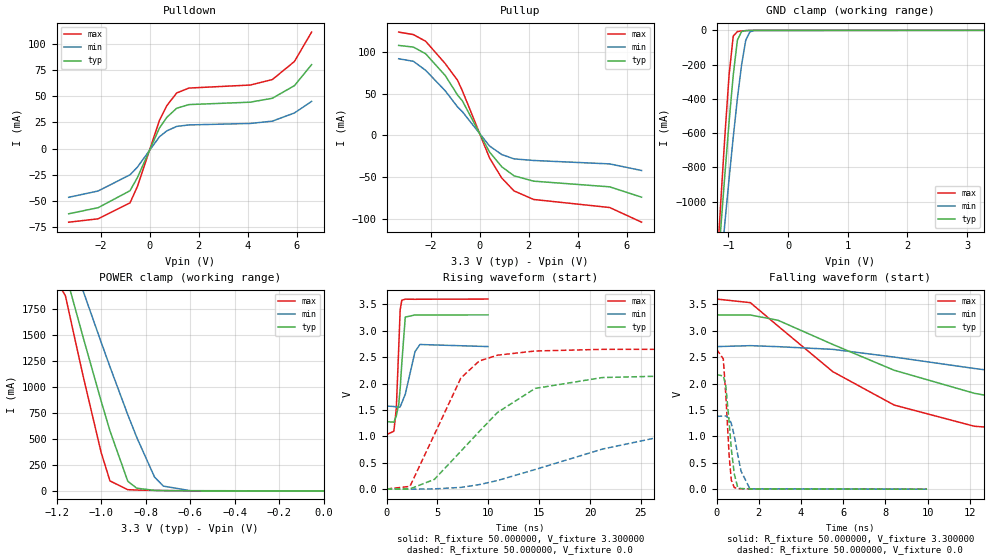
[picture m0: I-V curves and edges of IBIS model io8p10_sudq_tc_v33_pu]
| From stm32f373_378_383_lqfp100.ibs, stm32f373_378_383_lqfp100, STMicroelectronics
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|   Model io8p10_sudq_tc_v33_pu
[Model]  io8p10_sudq_tc_v33_pu
Model_type I/O
Polarity   Non-Inverting
Enable   Active-Low
Vinl =   0.990000V
Vinh =   2.310000V
Vmeas =  1.650000V
Cref =   50.000000pF
Rref =   100.000000M
Vref =   0.0V
C_comp   1.325200pF   1.251200pF   1.426700pF
[Temperature Range]   25.000000   0.125000k   -40.000000
[Pullup Reference]   3.300000V   2.700000V   3.600000V
[Pulldown Reference]   0.0V   0.0V   0.0V
[POWER Clamp Reference]   3.300000V   2.700000V   3.600000V
[GND Clamp Reference]   0.0V   0.0V   0.0V
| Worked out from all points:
|   slope of the pulldown table from 0 to 0.495 V, typ, clamps not added: 21.3 ohm
|   slope of the pullup table from 0 to 0.495 V, typ, clamps not added: 20.9 ohm
|   GND clamp passes 1 mA (typ) near -0.67 V on its own axis
|   POWER clamp passes 1 mA (typ) near -0.60 V on its own axis
|   rising waveform, R_fixture 50.000000, V_fixture 3.300000: 20-80 % time 415ps typ, 825ps min, 303ps max; typ from 1.28 V to 3.3 V
|   rising waveform, R_fixture 50.000000, V_fixture 0.0: 20-80 % time 6.87ns typ, 16.4ns min, 3.73ns max; typ from 0.001 V to 2.17 V
|   falling waveform, R_fixture 50.000000, V_fixture 3.300000: 20-80 % time 9.33ns typ, 15.5ns min, 5.81ns max; typ from 3.3 V to 1.28 V
|   falling waveform, R_fixture 50.000000, V_fixture 0.0: 20-80 % time 298ps typ, 414ps min, 226ps max; typ from 2.17 V to 0.001 V
[Pulldown]
|Voltage   I(typ)   I(min)   I(max)
-3.3V     -62mA      -46.3mA    -70mA
-2.1V     -56.2mA    -40.3mA    -66.8mA
-800mV    -40.05mA   -24.9mA    -51.58mA
-500mV    -27.57mA   -17.6mA    -36.07mA
400mV     19.71mA    11.36mA    27.01mA
700mV     29.83mA    16.93mA    40.97mA
1.1V      38.46mA    21.2mA     53.02mA
1.6V      41.98mA    22.62mA    57.7mA
4.1V      44.26mA    24mA       60.59mA
5V        48mA       26.2mA     65.8mA
5.9V      60mA       34mA       83mA
6.6V      80mA       45mA       111mA
[Pullup]
|Voltage   I(typ)   I(min)   I(max)
-3.3V     108mA      92mA       124mA
-2.7V     106mA      89mA       121mA
-2.2V     98mA       78.1mA     113mA
-1.4V     71.8mA     53.5mA     86.1mA
-900mV    48.5mA     34.23mA    66.14mA
-700mV    41.33mA    28.36mA    53.31mA
400mV     -19.77mA   -12.52mA   -26.8mA
900mV     -37.48mA   -22.89mA   -50.99mA
1.4V      -48.39mA   -28.06mA   -66.43mA
2.2V      -54.79mA   -29.98mA   -76.75mA
5.3V      -61.6mA    -34.1mA    -86.4mA
6.6V      -74mA      -42mA      -104mA
[GND_clamp]
|Voltage   I(typ)   I(min)   I(max)
-3.3V     -9.739A    -9.975A    -9.587A
-1.2V     -1.489A    -1.65A     -1.416A
-1.13V    -1.162A    -1.385A    -1.009A
-1.06V    -842.2mA   -1.125A    -616.9mA
-990mV    -537.1mA   -870.1mA   -263mA
-920mV    -262.4mA   -625.3mA   -33.96mA
-850mV    -56.94mA   -397.4mA   -7.08mA
-780mV    -7.011mA   -202.2mA   -3.71mA
-710mV    -1.778mA   -58.23mA   -1.736mA
-640mV    -550uA     -8.783mA   -542.4uA
-570mV    -109.8uA   -1.292mA   -86.89uA
3.28V     0A         0A         0A
[POWER_clamp]
|Voltage   I(typ)   I(min)   I(max)
-3.28V    9.897A     9.838A     9.594A
-1.16V    2.103A     2.419A     1.88A
-1.12V    1.788A     2.17A      1.488A
-1.08V    1.476A     1.923A     1.102A
-1V       868.2mA    1.435A     373.1mA
-960mV    578.3mA    1.196A     96.08mA
-880mV    93.25mA    734.2mA    12.03mA
-840mV    26.31mA    517.4mA    8.576mA
-760mV    5.12mA     134mA      5.134mA
-720mV    3.368mA    46.35mA    3.823mA
-600mV    1.018mA    2.575mA    1.086mA
0V        0A         0A         0A
[Ramp]
| variable   typ   min   max
dV/dt_r  1.30037/6.85912n   0.81167/16.46555n   1.58858/3.72403n
dV/dt_f  1.21374/9.31880n   0.66888/15.57260n   1.54152/5.80485n
R_load = 50.000000
[Rising Waveform]
R_fixture= 50.000000
V_fixture= 3.300000
V_fixture_min= 2.700000
V_fixture_max= 3.600000
|time   V(typ)   V(min)   V(max)
0s        1.277V     1.572V     1.031V
720.7ps   1.267V     1.565V     1.096V
961ps     1.385V     1.553V     1.52V
1.201ns   1.606V     1.55V      2.688V
1.341ns   1.904V     1.556V     3.397V
1.502ns   2.384V     1.633V     3.579V
1.842ns   3.259V     1.797V     3.598V
2.803ns   3.299V     2.605V     3.596V
3.283ns   3.299V     2.739V     3.597V
9.97ns    3.3V       2.7V       3.6V
[Rising Waveform]
R_fixture= 50.000000
V_fixture= 0.0
V_fixture_min= 0.0
V_fixture_max= 0.0
|time   V(typ)   V(min)   V(max)
0s        1.014mV    1.116mV    973.4uV
2.302ns   2.866mV    -2.155mV   50.76mV
4.705ns   183.5mV    3.128mV    1.034V
7.307ns   716.5mV    31.32mV    2.104V
9.109ns   1.09V      83.87mV    2.426V
10.91ns   1.452V     161.9mV    2.537V
14.61ns   1.907V     370.4mV    2.616V
21.22ns   2.113V     757.4mV    2.647V
31.43ns   2.16V      1.171V     2.649V
49.85ns   2.168V     1.379V     2.649V
[Falling Waveform]
R_fixture= 50.000000
V_fixture= 3.300000
V_fixture_min= 2.700000
V_fixture_max= 3.600000
|time   V(typ)   V(min)   V(max)
0s        3.3V       2.7V       3.6V
1.602ns   3.298V     2.718V     3.532V
2.903ns   3.2V       2.699V     3.092V
5.506ns   2.741V     2.648V     2.226V
8.408ns   2.253V     2.502V     1.594V
12.21ns   1.816V     2.286V     1.192V
15.82ns   1.558V     2.102V     1.088V
20.62ns   1.388V     1.915V     1.05V
35.14ns   1.283V     1.627V     1.032V
49.85ns   1.277V     1.572V     1.031V
[Falling Waveform]
R_fixture= 50.000000
V_fixture= 0.0
V_fixture_min= 0.0
V_fixture_max= 0.0
|time   V(typ)   V(min)   V(max)
0s        2.168V     1.379V     2.649V
320.3ps   2.146V     1.384V     2.469V
440.4ps   1.957V     1.386V     1.782V
600.6ps   1.257V     1.343V     615.9mV
700.7ps   760.8mV    1.243V     171.8mV
840.8ps   289.8mV    1.011V     32mV
1.001ns   35.36mV    659.4mV    11.73mV
1.161ns   12.95mV    341.7mV    6.946mV
1.582ns   4.539mV    7.242mV    5.834mV
9.97ns    1.014mV    1.116mV    973.4uV
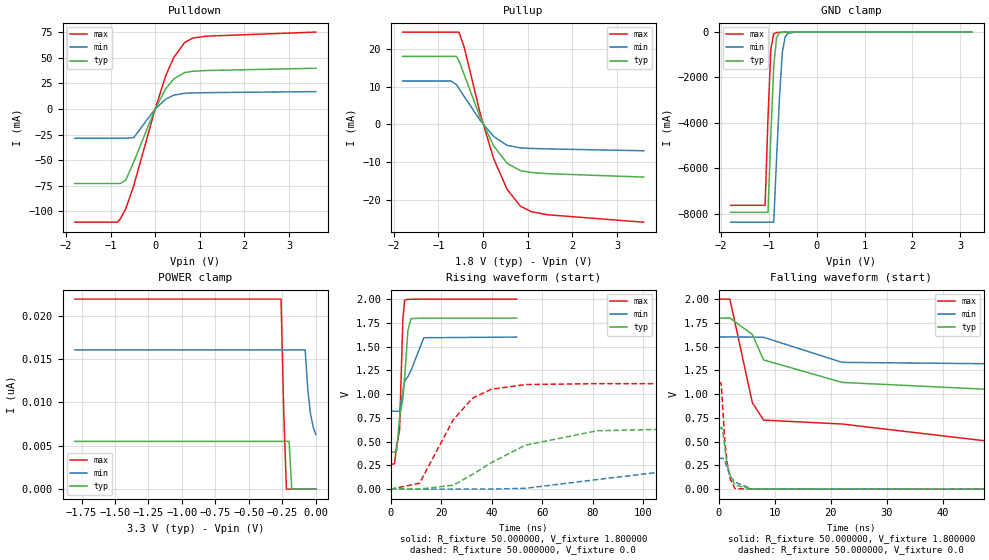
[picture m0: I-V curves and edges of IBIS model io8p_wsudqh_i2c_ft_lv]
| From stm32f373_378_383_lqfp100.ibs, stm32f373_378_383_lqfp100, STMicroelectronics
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|   Model io8p_wsudqh_i2c_ft_lv
[Model]  io8p_wsudqh_i2c_ft_lv
Model_type I/O
Polarity   Non-Inverting
Enable   Active-Low
Vinl =   0.540000V
Vinh =   1.260000V
Vmeas =  0.900000V
Cref =   40.000000pF
Rref =   100.000000M
Vref =   0.0V
C_comp   0.0F   0.0F   0.0F
[Temperature Range]   25.000000   0.140000k   -40.000000
[Pullup Reference]   1.800000V   1.600000V   2.000000V
[Pulldown Reference]   0.0V   0.0V   0.0V
[POWER Clamp Reference]   3.300000V   2.700000V   3.600000V
[GND Clamp Reference]   0.0V   0.0V   0.0V
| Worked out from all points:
|   slope of the pulldown table from 0 to 0.27 V, typ, clamps not added: 12.4 ohm
|   slope of the pullup table from 0 to 0.27 V, typ, clamps not added: 42.7 ohm
|   GND clamp passes 1 mA (typ) near -0.61 V on its own axis
|   rising waveform, R_fixture 50.000000, V_fixture 1.800000: 20-80 % time 3.36ns typ, 5.5ns min, 1.18ns max; typ from 0.39 V to 1.8 V
|   rising waveform, R_fixture 50.000000, V_fixture 0.0: 20-80 % time 28.5ns typ, 60ns min, 14.6ns max; typ from 0 V to 0.643 V
|   falling waveform, R_fixture 50.000000, V_fixture 1.800000: 20-80 % time 95.2ns typ, 220ns min, 38.6ns max; typ from 1.8 V to 0.39 V
|   falling waveform, R_fixture 50.000000, V_fixture 0.0: 20-80 % time 1.17ns typ, 1.76ns min, 975ps max; typ from 0.643 V to 0 V
[Pulldown]
|Voltage   I(typ)   I(min)   I(max)
-1.8V     -72.82mA   -28.67mA   -110.6mA
-840mV    -72.82mA   -28.67mA   -110.6mA
-780mV    -72.82mA   -28.67mA   -107.2mA
-660mV    -69.63mA   -28.67mA   -97.66mA
-480mV    -51.79mA   -27.98mA   -74.89mA
0V        0A         0A         0A
240mV     19.98mA    9.621mA    32.82mA
420mV     29.47mA    13.52mA    50.45mA
660mV     35.49mA    15.27mA    64.82mA
840mV     36.76mA    15.6mA     69.15mA
1.14V     37.47mA    15.86mA    71.04mA
3.6V      39.71mA    16.9mA     75.01mA
[Pullup]
|Voltage   I(typ)   I(min)   I(max)
-1.8V     18.1mA     11.56mA    24.57mA
-720mV    18.1mA     11.56mA    24.57mA
-600mV    18.1mA     10.62mA    24.57mA
-540mV    16.94mA    9.59mA     24.54mA
-420mV    13.15mA    7.37mA     20.4mA
-60mV     1.723mA    985.9uA    2.671mA
240mV     -5.743mA   -3.226mA   -9.221mA
540mV     -10.36mA   -5.558mA   -17.32mA
840mV     -12.32mA   -6.245mA   -21.78mA
1.08V     -12.77mA   -6.379mA   -23.2mA
1.44V     -13.09mA   -6.504mA   -24.02mA
3.6V      -14mA      -7mA       -26mA
[GND_clamp]
|Voltage   I(typ)   I(min)   I(max)
-1.8V     -7.944A    -8.38A     -7.635A
-1.08V    -7.944A    -8.38A     -7.635A
-1.02V    -7.944A    -8.38A     -3.818A
-960mV    -4.573A    -8.38A     -759.3mA
-900mV    -1.502A    -8.38A     -75.03mA
-840mV    -238mA     -5.574A    -20.4mA
-780mV    -36.12mA   -2.918A    -12.65mA
-720mV    -7.999mA   -894.2mA   -8.064mA
-660mV    -2.38mA    -209.5mA   -4.357mA
-600mV    -722.7uA   -49.62mA   -1.754mA
-420mV    -7.04uA    -712.1uA   -10.35uA
3.24V     0A         5.34nA     0A
[POWER_clamp]
|Voltage   I(typ)   I(min)   I(max)
-1.8V     5.515nA    16.06nA    21.93nA
-260mV    5.515nA    16.06nA    21.93nA
-240mV    5.515nA    16.06nA    8.985nA
-220mV    5.515nA    16.06nA    0A
-200mV    5.515nA    16.06nA    0A
-180mV    0A         16.06nA    0A
-80mV     0A         16.06nA    0A
-60mV     0A         11.42nA    0A
-40mV     0A         8.703nA    0A
-20mV     0A         7.161nA    0A
0V        0A         6.282nA    0A
[Ramp]
| variable   typ   min   max
dV/dt_r  0.38563/28.42811n   0.19292/59.39374n   0.66606/14.53010n
dV/dt_f  0.84326/94.87785n   0.39602/0.18874u   1.04521/38.27709n
R_load = 50.000000
[Rising Waveform]
R_fixture= 50.000000
V_fixture= 1.800000
V_fixture_min= 1.600000
V_fixture_max= 2.000000
|time   V(typ)   V(min)   V(max)
0s        389.9mV    821mV      258mV
1.502ns   388.9mV    819.7mV    267.3mV
2.402ns   406.2mV    818.3mV    463.2mV
3.504ns   755mV      820.6mV    617.3mV
4.805ns   944.7mV    1.022V     1.783V
5.506ns   1.17V      1.138V     1.988V
6.807ns   1.668V     1.183V     1.997V
8.008ns   1.794V     1.247V     1.998V
13.11ns   1.8V       1.593V     1.999V
49.85ns   1.8V       1.6V       2V
[Rising Waveform]
R_fixture= 50.000000
V_fixture= 0.0
V_fixture_min= 0.0
V_fixture_max= 0.0
|time   V(typ)   V(min)   V(max)
0s        973.9pV    20.22nV    702pV
11.41ns   -342.5uV   -776.4uV   62.09mV
24.72ns   40.77mV    -74.15uV   728.8mV
32.33ns   153.9mV    6.2uV      956.4mV
39.94ns   280.4mV    292.3uV    1.052V
53.25ns   462mV      8.25mV     1.1V
81.78ns   614.1mV    100.7mV    1.11V
131.2ns   642.1mV    256mV      1.11V
182.6ns   642.8mV    309.4mV    1.11V
947.1ns   642.7mV    322.7mV    1.11V
[Falling Waveform]
R_fixture= 50.000000
V_fixture= 1.800000
V_fixture_min= 1.600000
V_fixture_max= 2.000000
|time   V(typ)   V(min)   V(max)
0s        1.8V       1.6V       2V
2.002ns   1.801V     1.602V     2V
6.006ns   1.628V     1.6V       911.3mV
8.008ns   1.36V      1.598V     726.5mV
22.02ns   1.123V     1.334V     685.3mV
78.08ns   966.2mV    1.303V     296.2mV
116.1ns   543mV      1.296V     266.8mV
170.2ns   419.4mV    1.192V     259.3mV
340.3ns   390.6mV    850.8mV    257.9mV
997ns     389.9mV    821mV      258mV
[Falling Waveform]
R_fixture= 50.000000
V_fixture= 0.0
V_fixture_min= 0.0
V_fixture_max= 0.0
|time   V(typ)   V(min)   V(max)
0s        642.7mV    322.7mV    1.11V
400.4ps   646.9mV    323mV      1.119V
500.5ps   650.7mV    324.1mV    1.086V
700.7ps   624.1mV    327.7mV    889.6mV
1.101ns   438.9mV    298.8mV    513.3mV
1.502ns   258.1mV    226.9mV    286.1mV
2.102ns   132.4mV    132.6mV    100.1mV
2.903ns   42.85mV    74.38mV    6.502mV
5.906ns   1.079mV    1.846mV    589.7uV
49.85ns   973.9pV    20.22nV    702pV
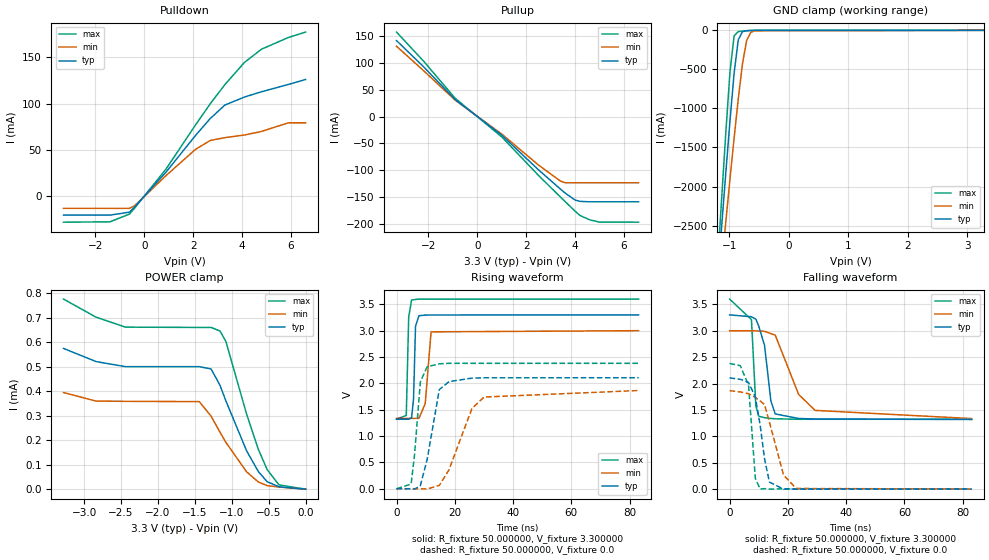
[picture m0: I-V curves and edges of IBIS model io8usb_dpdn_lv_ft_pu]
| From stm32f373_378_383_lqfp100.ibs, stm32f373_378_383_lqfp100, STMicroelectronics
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|   Model io8usb_dpdn_lv_ft_pu
[Model]  io8usb_dpdn_lv_ft_pu
Model_type I/O
Polarity   Non-Inverting
Enable   Active-Low
Vinl =   0.990000V
Vinh =   2.310000V
Vmeas =  1.650000V
Cref =   50.000000pF
Rref =   100.000000M
Vref =   0.0V
C_comp   5.029800pF   4.851400pF   5.238000pF
[Temperature Range]   25.000000   0.125000k   -40.000000
[Pullup Reference]   3.300000V   3.000000V   3.600000V
[Pulldown Reference]   0.0V   0.0V   0.0V
[POWER Clamp Reference]   3.300000V   3.000000V   3.600000V
[GND Clamp Reference]   0.0V   0.0V   0.0V
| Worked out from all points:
|   slope of the pulldown table from 0 to 0.495 V, typ, clamps not added: 34.5 ohm
|   slope of the pullup table from 0 to 0.495 V, typ, clamps not added: 30.3 ohm
|   GND clamp passes 1 mA (typ) near -0.59 V on its own axis
|   rising waveform, R_fixture 50.000000, V_fixture 3.300000: 20-80 % time 563ps typ, 845ps min, 473ps max; typ from 1.32 V to 3.3 V
|   rising waveform, R_fixture 50.000000, V_fixture 0.0: 20-80 % time 3.84ns typ, 7.53ns min, 2.08ns max; typ from 0.002 V to 2.11 V
|   falling waveform, R_fixture 50.000000, V_fixture 3.300000: 20-80 % time 3.08ns typ, 7.44ns min, 1.2ns max; typ from 3.3 V to 1.32 V
|   falling waveform, R_fixture 50.000000, V_fixture 0.0: 20-80 % time 3.27ns typ, 5.44ns min, 1.75ns max; typ from 2.11 V to 0.002 V
[Pulldown]
|Voltage   I(typ)   I(min)   I(max)
-3.3V     -20.2mA    -12.85mA   -27.8mA
-1.4V     -20.2mA    -12.85mA   -27.4mA
-600mV    -16.97mA   -12.85mA   -19mA
-400mV    -11.64mA   -10.26mA   -12.92mA
900mV     26.39mA    22.6mA     29.76mA
2.1V      65.72mA    50.72mA    77.05mA
2.7V      83.87mA    60.28mA    99.79mA
3.3V      98.46mA    63.32mA    120.5mA
4.1V      107.1mA    66.16mA    144.4mA
4.8V      112.8mA    70.03mA    158.7mA
5.9V      120.7mA    79.32mA    171.3mA
6.6V      126mA      79.32mA    177.1mA
[Pullup]
|Voltage   I(typ)   I(min)   I(max)
-3.3V     140.7mA    130.2mA    156.5mA
-2.2V     92.45mA    85.22mA    102.9mA
-900mV    31.27mA    30.18mA    33.72mA
1V        -34.43mA   -32.42mA   -37.73mA
2.5V      -98.62mA   -89.74mA   -108.9mA
3.4V      -134.4mA   -119.6mA   -149.1mA
3.6V      -142mA     -122.8mA   -157.9mA
4V        -154.8mA   -122.8mA   -175.4mA
4.2V      -157.3mA   -122.8mA   -183.4mA
4.6V      -158.1mA   -122.8mA   -191.5mA
5V        -158.1mA   -122.8mA   -195.7mA
6.6V      -158.1mA   -122.8mA   -195.9mA
[GND_clamp]
|Voltage   I(typ)   I(min)   I(max)
-3.3V     -9.706A    -9.44A     -9.292A
-1.2V     -3.211A    -3.572A    -3.02A
-1.13V    -2.511A    -3.009A    -2.153A
-1.06V    -1.824A    -2.453A    -1.311A
-990mV    -1.16A     -1.907A    -534mA
-920mV    -548mA     -1.377A    -70.08mA
-850mV    -120.4mA   -876.3mA   -15.9mA
-780mV    -17.66mA   -431.2mA   -9.191mA
-710mV    -5.44mA    -131mA     -5.02mA
-640mV    -2.077mA   -25.74mA   -2.003mA
-570mV    -540.4uA   -6.318mA   -433.9uA
3.28V     0A         0A         0A
[POWER_clamp]
|Voltage   I(typ)   I(min)   I(max)
-3.28V    574uA      394.1uA    775.2uA
-2.84V    520.4uA    359.2uA    701.6uA
-2.44V    499.5uA    358.1uA    660.7uA
-1.44V    499.5uA    357uA      659.5uA
-1.28V    490.2uA    297.6uA    659.5uA
-1.16V    423.6uA    232.7uA    645.1uA
-1.08V    360.3uA    191uA      602.6uA
-800mV    157uA      71.03uA    307.1uA
-640mV    71.83uA    29.17uA    162.4uA
-520mV    30.52uA    14.41uA    79.51uA
-360mV    9.626uA    8.7uA      17.31uA
0V        0A         0A         0A
[Ramp]
| variable   typ   min   max
dV/dt_r  1.26347/3.83638n   1.11781/7.52247n   1.42742/2.07992n
dV/dt_f  1.18410/3.07267n   0.99888/7.43784n   1.36692/1.62117n
R_load = 50.000000
[Rising Waveform]
R_fixture= 50.000000
V_fixture= 3.300000
V_fixture_min= 3.000000
V_fixture_max= 3.600000
|time   V(typ)   V(min)   V(max)
0s        1.319V     1.336V     1.323V
3.337ns   1.319V     1.336V     1.391V
4.171ns   1.319V     1.336V     3.259V
5.172ns   1.352V     1.335V     3.583V
5.839ns   1.71V      1.335V     3.588V
6.507ns   3.082V     1.335V     3.592V
7.674ns   3.284V     1.335V     3.6V
9.843ns   3.296V     1.616V     3.598V
11.85ns   3.298V     2.978V     3.599V
83.08ns   3.3V       3V         3.6V
[Rising Waveform]
R_fixture= 50.000000
V_fixture= 0.0
V_fixture_min= 0.0
V_fixture_max= 0.0
|time   V(typ)   V(min)   V(max)
0s        1.717mV    1.585mV    1.964mV
5.005ns   -793.3uV   1.588mV    89.28mV
6.173ns   -6.852mV   1.591mV    646.1mV
8.175ns   60.79mV    955.9uV    2.032V
10.51ns   558.2mV    -3.556mV   2.316V
14.68ns   1.883V     65.49mV    2.372V
18.02ns   2.034V     362.2mV    2.381V
25.86ns   2.1V       1.522V     2.381V
30.03ns   2.106V     1.741V     2.381V
83.08ns   2.107V     1.865V     2.381V
[Falling Waveform]
R_fixture= 50.000000
V_fixture= 3.300000
V_fixture_min= 3.000000
V_fixture_max= 3.600000
|time   V(typ)   V(min)   V(max)
0s        3.3V       3V         3.6V
7.508ns   3.265V     3V         3.21V
9.009ns   3.219V     2.997V     1.575V
10.01ns   3.088V     2.995V     1.381V
12.01ns   2.718V     2.989V     1.353V
14.18ns   1.667V     2.946V     1.338V
15.68ns   1.424V     2.916V     1.332V
23.69ns   1.338V     1.794V     1.323V
29.36ns   1.328V     1.491V     1.323V
83.08ns   1.319V     1.336V     1.323V
[Falling Waveform]
R_fixture= 50.000000
V_fixture= 0.0
V_fixture_min= 0.0
V_fixture_max= 0.0
|time   V(typ)   V(min)   V(max)
0s        2.107V     1.865V     2.381V
3.67ns    2.08V      1.841V     2.338V
6.507ns   2.019V     1.807V     1.968V
8.842ns   1.742V     1.734V     200.7mV
10.51ns   1.203V     1.671V     169.7uV
12.01ns   568.9mV    1.598V     9.146mV
13.68ns   132.5mV    1.266V     -1.1mV
18.52ns   -110.6uV   266.5mV    7.506mV
22.86ns   1.002mV    11.64mV    2.888mV
83.08ns   1.717mV    1.585mV    1.964mV
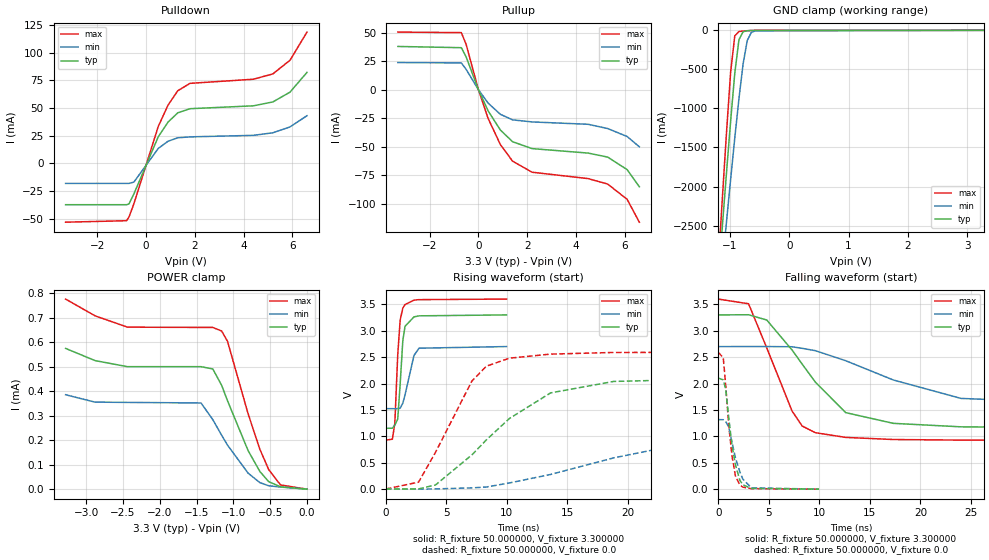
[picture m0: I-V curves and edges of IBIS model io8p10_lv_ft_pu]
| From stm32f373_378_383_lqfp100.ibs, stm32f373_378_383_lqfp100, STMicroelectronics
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|   Model io8p10_lv_ft_pu
[Model]  io8p10_lv_ft_pu
Model_type I/O
Polarity   Non-Inverting
Enable   Active-Low
Vinl =   0.990000V
Vinh =   2.310000V
Vmeas =  1.650000V
Cref =   50.000000pF
Rref =   100.000000M
Vref =   0.0V
C_comp   5.028100pF   4.857200pF   5.254400pF
[Temperature Range]   25.000000   0.125000k   -40.000000
[Pullup Reference]   3.300000V   2.700000V   3.600000V
[Pulldown Reference]   0.0V   0.0V   0.0V
[POWER Clamp Reference]   3.300000V   2.700000V   3.600000V
[GND Clamp Reference]   0.0V   0.0V   0.0V
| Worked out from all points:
|   slope of the pulldown table from 0 to 0.495 V, typ, clamps not added: 20.9 ohm
|   slope of the pullup table from 0 to 0.495 V, typ, clamps not added: 22.2 ohm
|   GND clamp passes 1 mA (typ) near -0.59 V on its own axis
|   rising waveform, R_fixture 50.000000, V_fixture 3.300000: 20-80 % time 375ps typ, 705ps min, 338ps max; typ from 1.15 V to 3.3 V
|   rising waveform, R_fixture 50.000000, V_fixture 0.0: 20-80 % time 6.33ns typ, 15ns min, 3.53ns max; typ from 0.001 V to 2.1 V
|   falling waveform, R_fixture 50.000000, V_fixture 3.300000: 20-80 % time 5.37ns typ, 11ns min, 3.28ns max; typ from 3.3 V to 1.15 V
|   falling waveform, R_fixture 50.000000, V_fixture 0.0: 20-80 % time 885ps typ, 1.08ns min, 741ps max; typ from 2.1 V to 0.001 V
[Pulldown]
|Voltage   I(typ)   I(min)   I(max)
-3.3V     -37.45mA   -18.2mA    -53.24mA
-800mV    -37.45mA   -18.2mA    -51.9mA
-700mV    -36.7mA    -18.2mA    -48.48mA
-500mV    -27.71mA   -17.01mA   -36.66mA
500mV     23.91mA    13.38mA    33.24mA
900mV     37.17mA    19.88mA    52.48mA
1.3V      45.55mA    23.01mA    65.5mA
1.8V      49.29mA    23.83mA    72.18mA
4.4V      51.88mA    25.21mA    75.91mA
5.2V      55.41mA    27.53mA    80.72mA
5.9V      64.2mA     32.82mA    93.01mA
6.6V      82.13mA    42.97mA    118.5mA
[Pullup]
|Voltage   I(typ)   I(min)   I(max)
-3.3V     37.85mA    23.75mA    50.43mA
-700mV    36.77mA    23.48mA    49.96mA
-500mV    28.57mA    17.67mA    39.46mA
0V        100fA      16.1pA     0A
400mV     -18.61mA   -11.78mA   -25.23mA
900mV     -35.28mA   -21.54mA   -48mA
1.4V      -45.54mA   -26.4mA    -62.54mA
2.2V      -51.57mA   -28.22mA   -72.25mA
4.5V      -55.5mA    -30.3mA    -77.84mA
5.3V      -59mA      -34mA      -82.6mA
6.1V      -70mA      -41mA      -96mA
6.6V      -85mA      -50mA      -116mA
[GND_clamp]
|Voltage   I(typ)   I(min)   I(max)
-3.3V     -9.706A    -9.438A    -9.292A
-1.2V     -3.211A    -3.571A    -3.02A
-1.13V    -2.511A    -3.008A    -2.153A
-1.06V    -1.824A    -2.453A    -1.311A
-990mV    -1.16A     -1.907A    -534mA
-920mV    -548mA     -1.377A    -70.08mA
-850mV    -120.4mA   -875.9mA   -15.9mA
-780mV    -17.66mA   -430.9mA   -9.191mA
-710mV    -5.44mA    -130.8mA   -5.02mA
-640mV    -2.077mA   -25.65mA   -2.003mA
-570mV    -540.4uA   -6.293mA   -433.9uA
3.28V     0A         0A         0A
[POWER_clamp]
|Voltage   I(typ)   I(min)   I(max)
-3.28V    574uA      385.1uA    775.2uA
-2.88V    524.3uA    354.9uA    706.9uA
-2.44V    499.5uA    353.8uA    660.7uA
-1.44V    499.5uA    351.5uA    659.5uA
-1.28V    490.2uA    283.5uA    659.5uA
-1.16V    423.6uA    220uA      645.1uA
-1.08V    360.3uA    179.6uA    602.6uA
-800mV    157uA      65.19uA    307.1uA
-640mV    71.83uA    26.56uA    162.4uA
-520mV    30.52uA    13.8uA     79.51uA
-360mV    9.626uA    8.662uA    17.31uA
0V        0A         0A         0A
[Ramp]
| variable   typ   min   max
dV/dt_r  1.26216/6.32116n   0.77944/15.00186n   1.55427/3.52754n
dV/dt_f  1.28874/5.36415n   0.69726/10.98636n   1.60394/3.27797n
R_load = 50.000000
[Rising Waveform]
R_fixture= 50.000000
V_fixture= 3.300000
V_fixture_min= 2.700000
V_fixture_max= 3.600000
|time   V(typ)   V(min)   V(max)
0s        1.152V     1.524V     926.8mV
540.5ps   1.153V     1.523V     944.7mV
740.7ps   1.211V     1.522V     1.247V
981ps     1.326V     1.524V     2.541V
1.181ns   1.987V     1.531V     3.199V
1.401ns   2.812V     1.626V     3.429V
1.582ns   3.083V     1.782V     3.496V
2.322ns   3.262V     2.531V     3.58V
2.743ns   3.282V     2.669V     3.589V
9.97ns    3.3V       2.7V       3.6V
[Rising Waveform]
R_fixture= 50.000000
V_fixture= 0.0
V_fixture_min= 0.0
V_fixture_max= 0.0
|time   V(typ)   V(min)   V(max)
0s        1.075mV    1.208mV    1.035mV
2.703ns   3.133mV    -2.083mV   131.1mV
4.104ns   77.86mV    2.626mV    695.9mV
7.107ns   647mV      22.11mV    2.046V
8.308ns   931.9mV    38.56mV    2.328V
10.21ns   1.337V     115.6mV    2.48V
13.61ns   1.822V     276.4mV    2.557V
18.82ns   2.039V     590.4mV    2.588V
29.93ns   2.101V     1.103V     2.592V
49.85ns   2.105V     1.317V     2.592V
[Falling Waveform]
R_fixture= 50.000000
V_fixture= 3.300000
V_fixture_min= 2.700000
V_fixture_max= 3.600000
|time   V(typ)   V(min)   V(max)
0s        3.3V       2.7V       3.6V
3.003ns   3.303V     2.701V     3.511V
4.805ns   3.203V     2.701V     2.674V
7.307ns   2.635V     2.697V     1.48V
8.308ns   2.368V     2.667V     1.196V
9.61ns    2.028V     2.623V     1.07V
12.61ns   1.45V      2.433V     980.9mV
17.32ns   1.247V     2.068V     940.9mV
24.02ns   1.181V     1.719V     929.6mV
49.85ns   1.152V     1.524V     926.8mV
[Falling Waveform]
R_fixture= 50.000000
V_fixture= 0.0
V_fixture_min= 0.0
V_fixture_max= 0.0
|time   V(typ)   V(min)   V(max)
0s        2.105V     1.317V     2.592V
500.5ps   2.07V      1.316V     2.49V
740.7ps   1.892V     1.284V     1.973V
1.041ns   1.359V     1.176V     1.215V
1.361ns   836mV      896.1mV    635.4mV
1.702ns   467.4mV    598.3mV    253mV
2.142ns   169.2mV    327.6mV    80.28mV
2.442ns   82.47mV    190.5mV    39.2mV
3.283ns   15.07mV    26.43mV    10.96mV
9.97ns    1.075mV    1.208mV    1.035mV
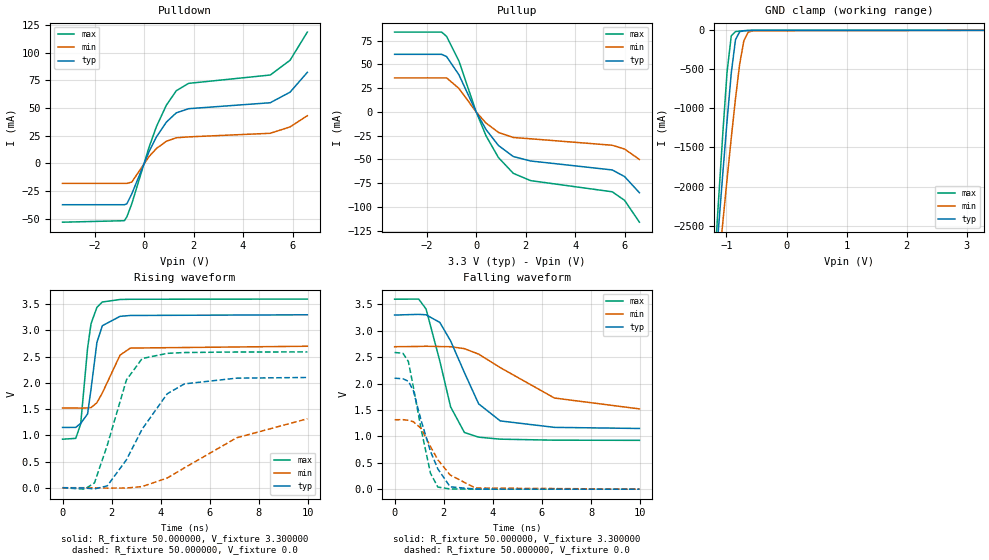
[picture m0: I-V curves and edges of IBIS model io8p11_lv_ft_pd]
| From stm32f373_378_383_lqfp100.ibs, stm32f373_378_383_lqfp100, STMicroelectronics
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|   Model io8p11_lv_ft_pd
[Model]  io8p11_lv_ft_pd
Model_type I/O
Polarity   Non-Inverting
Enable   Active-Low
Vinl =   0.990000V
Vinh =   2.310000V
Vmeas =  1.650000V
Cref =   30.000000pF
Rref =   100.000000M
Vref =   0.0V
C_comp   5.028100pF   4.857200pF   5.254400pF
[Temperature Range]   25.000000   0.125000k   -40.000000
[Pullup Reference]   3.300000V   2.700000V   3.600000V
[Pulldown Reference]   0.0V   0.0V   0.0V
[POWER Clamp Reference]   3.300000V   2.700000V   3.600000V
[GND Clamp Reference]   0.0V   0.0V   0.0V
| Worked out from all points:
|   slope of the pulldown table from 0 to 0.495 V, typ, clamps not added: 20.9 ohm
|   slope of the pullup table from 0 to 0.495 V, typ, clamps not added: 22.2 ohm
|   GND clamp passes 1 mA (typ) near -0.59 V on its own axis
|   rising waveform, R_fixture 50.000000, V_fixture 3.300000: 20-80 % time 378ps typ, 722ps min, 341ps max; typ from 1.15 V to 3.3 V
|   rising waveform, R_fixture 50.000000, V_fixture 0.0: 20-80 % time 1.6ns typ, 3.09ns min, 980ps max; typ from 0 V to 2.1 V
|   falling waveform, R_fixture 50.000000, V_fixture 3.300000: 20-80 % time 1.26ns typ, 2.6ns min, 827ps max; typ from 3.3 V to 1.15 V
|   falling waveform, R_fixture 50.000000, V_fixture 0.0: 20-80 % time 849ps typ, 1.07ns min, 649ps max; typ from 2.1 V to 0 V
[Pulldown]
|Voltage   I(typ)   I(min)   I(max)
-3.3V     -37.45mA   -18.2mA    -53.24mA
-800mV    -37.45mA   -18.2mA    -51.9mA
-700mV    -36.7mA    -18.2mA    -48.48mA
-500mV    -27.71mA   -17.01mA   -36.66mA
200mV     10.57mA    6.084mA    14.57mA
500mV     23.91mA    13.38mA    33.24mA
900mV     37.17mA    19.88mA    52.48mA
1.3V      45.55mA    23.01mA    65.5mA
1.8V      49.29mA    23.83mA    72.18mA
5.1V      54.68mA    27.07mA    79.72mA
5.9V      64.2mA     32.82mA    93.01mA
6.6V      82.13mA    42.97mA    118.5mA
[Pullup]
|Voltage   I(typ)   I(min)   I(max)
-3.3V     60.68mA    35.91mA    84.09mA
-1.4V     60.68mA    35.91mA    84.09mA
-1.2V     58.38mA    35.91mA    79.68mA
-700mV    39.19mA    24.86mA    53.71mA
0V        0A         0A         0A
400mV     -18.61mA   -11.78mA   -25.23mA
900mV     -35.28mA   -21.55mA   -48mA
1.5V      -46.91mA   -26.86mA   -64.57mA
2.2V      -51.57mA   -28.22mA   -72.25mA
5.5V      -61mA      -35mA      -84mA
6V        -68mA      -39mA      -93mA
6.6V      -85mA      -50mA      -116mA
[GND_clamp]
|Voltage   I(typ)   I(min)   I(max)
-3.3V     -9.706A    -9.438A    -9.292A
-1.2V     -3.211A    -3.571A    -3.02A
-1.13V    -2.511A    -3.008A    -2.153A
-1.06V    -1.824A    -2.453A    -1.311A
-990mV    -1.16A     -1.907A    -534mA
-920mV    -548mA     -1.377A    -70.1mA
-850mV    -120.5mA   -875.9mA   -15.92mA
-780mV    -17.67mA   -430.9mA   -9.208mA
-710mV    -5.454mA   -130.8mA   -5.036mA
-640mV    -2.091mA   -25.66mA   -2.018mA
-570mV    -553.8uA   -6.304mA   -449uA
3.28V     83.63uA    63.63uA    93.37uA
[POWER_clamp]
|Voltage   I(typ)   I(min)   I(max)
-3.28V    0A         0A         0A
0V        0A         0A         0A
[Ramp]
| variable   typ   min   max
dV/dt_r  1.26096/1.59417n   0.73422/3.06331n   1.55370/0.97888n
dV/dt_f  1.28802/1.26424n   0.68454/2.59465n   1.60431/0.82633n
R_load = 50.000000
[Rising Waveform]
R_fixture= 50.000000
V_fixture= 3.300000
V_fixture_min= 2.700000
V_fixture_max= 3.600000
|time   V(typ)   V(min)   V(max)
0s        1.15V      1.521V     925.1mV
540.5ps   1.151V     1.52V      941.5mV
740.7ps   1.228V     1.519V     1.22V
1.021ns   1.408V     1.523V     2.663V
1.161ns   1.879V     1.528V     3.129V
1.401ns   2.773V     1.622V     3.441V
1.622ns   3.091V     1.808V     3.543V
2.342ns   3.269V     2.529V     3.591V
2.763ns   3.286V     2.664V     3.595V
9.97ns    3.299V     2.699V     3.599V
[Rising Waveform]
R_fixture= 50.000000
V_fixture= 0.0
V_fixture_min= 0.0
V_fixture_max= 0.0
|time   V(typ)   V(min)   V(max)
0s        -11.23uV   -20.25uV   -7.868uV
900.9ps   -5.832mV   51.02uV    -27.72mV
1.301ns   -22.96mV   -1.285mV   92.1mV
1.822ns   34.81mV    -8.165mV   809.8mV
2.603ns   532.8mV    -6.383mV   2.056V
3.243ns   1.118V     22.05mV    2.465V
4.264ns   1.792V     185mV      2.563V
4.965ns   1.981V     379mV      2.579V
7.087ns   2.09V      951.8mV    2.589V
9.97ns    2.103V     1.315V     2.59V
[Falling Waveform]
R_fixture= 50.000000
V_fixture= 3.300000
V_fixture_min= 2.700000
V_fixture_max= 3.600000
|time   V(typ)   V(min)   V(max)
0s        3.299V     2.699V     3.599V
981ps     3.312V     2.704V     3.602V
1.281ns   3.304V     2.708V     3.414V
1.842ns   3.159V     2.702V     2.427V
2.282ns   2.807V     2.699V     1.558V
2.843ns   2.209V     2.662V     1.074V
3.423ns   1.616V     2.559V     985.4mV
4.304ns   1.293V     2.303V     947.3mV
6.507ns   1.171V     1.727V     928.2mV
9.97ns    1.15V      1.521V     925.1mV
[Falling Waveform]
R_fixture= 50.000000
V_fixture= 0.0
V_fixture_min= 0.0
V_fixture_max= 0.0
|time   V(typ)   V(min)   V(max)
0s        2.103V     1.315V     2.59V
340.3ps   2.092V     1.317V     2.574V
560.6ps   2.044V     1.305V     2.419V
760.8ps   1.87V      1.279V     1.944V
1.081ns   1.3V       1.151V     1.134V
1.461ns   716.4mV    806.7mV    301.6mV
1.762ns   382.9mV    557.6mV    39.54mV
2.262ns   44.32mV    268.9mV    4.058mV
3.283ns   1.927mV    22.27mV    881.8uV
9.97ns    -11.23uV   -20.25uV   -7.868uV
